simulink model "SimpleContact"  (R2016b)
settings: Solver=ode14x  StartTime=0.0  StopTime=1.5  FixedStep=1e-3  RelTol=1e-3  AbsTol=1e-4  EnableMultiTasking=on
PreLoadFcn:
  | SimpleContact_param
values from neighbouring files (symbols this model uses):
  bn = 50    [SimpleContact_param.m]    (also in BipedRobot_param.m)
  bt = 50    [SimpleContact_param.m]    (also in BipedRobot_param.m)
  kn = 5000    [SimpleContact_param.m]    (also in BipedRobot_param.m)
  kt = 5000    [SimpleContact_param.m]    (also in BipedRobot_param.m)
  mu_d = 0.8    [SimpleContact_param.m]    (also in BipedRobot_param.m)
  mu_s = 2    [SimpleContact_param.m]    (also in BipedRobot_param.m)
  N = 100    [initialize_para.m]    (also in main.m = walk_para.N; walk_parameter.m = 5)
  s = robot_para.s    [kinematics_calc.m]    (also in plot_graph.m; robot_parameter.m = 40; robot_view.m)
  zvt = 1e-3    (= 0.001)    [SimpleContact_param.m]    (also in BipedRobot_param.m)
undefined symbols (not defined in the file or in its folder): deg, kg, m
libraries: mblibv1 x18

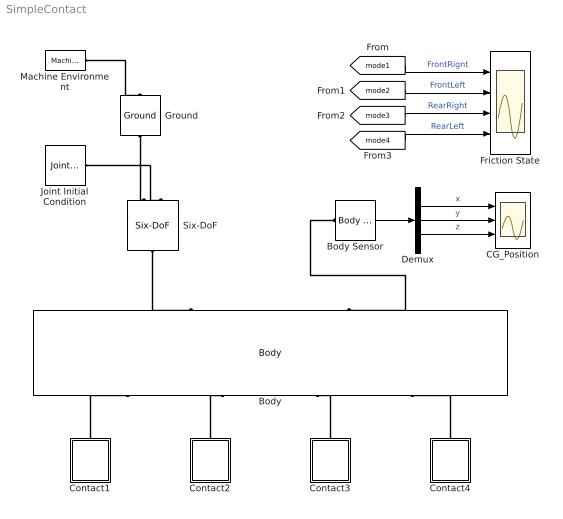
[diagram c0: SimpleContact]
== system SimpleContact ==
  Body : mblibv1/Bodies/Body  LConnTagsString=CS2|CS3|CS4|CS5  RConnTagsString=CG|CS1  UpdateFromCAD=off  DialogClass=MechanicalBodyBlock  Mass=1.4  MassUnits=kg  InertiaUnits=kg*m^2  Inertia=1.4/12*diag([0.065^2+0.02^2 0.095^2+0.02^2 0.095^2+0.065^2])  Shape=Cylinder  ShapeDims=[1 1]  ShapeUnits=m  ShapeUse=false  Density=1  DensityUnits=kg/m^3  DensityUse=false  GraphicsMode=MACHINE_DEFAULT  BodyColorSelMode=MACHINE_DEFAULT  BodyColor=[1;0;0]  AttachedToCS=CG  CG=Right$CG$[0 0 100]$WORLD$WORLD$mm$[30 -30 30]$Euler X-Y-Z$deg$WORLD$true  WorkingFrames=Right$CS1$[0 0 0]$CG$CG$mm$[0 0 0]$Euler X-Y-Z$deg$CG$true#Left$CS2$[47.5 32.5 -10]$CG$CG$mm$[0 0 0]$Euler X-Y-Z$deg$CG$true#Left$CS3$[47.5 -32.5 -10]$CG$CG$mm$[0 0 0]$Euler X-Y-Z$deg$CG$true#Left$CS4$[-47.5 32.5 -10]$CG$CG$mm$[0 0 0]$Euler X-Y-Z$deg$CG$true#Left$CS5$[-47.5 -32.5 -10]$CG$CG$mm$[0 0 0]$Euler X-Y-Z$deg$CG$true#Left$CS6$[47.5 32.5 10]$CG$CG$mm$[0 0 0]$Euler X-Y-Z$deg$CG$false#Left$CS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  CGPos=[0 0 100]  CGRot=[30 -30 30]  CS0Pos=[]  CS0Rot=[]  CS1Pos=[0 0 0]  CS1Rot=[0 0 0]  CS2Pos=[47.5 32.5 -10]  CS2Rot=[0 0 0]  CS3Pos=[47.5 -32.5 -10]  CS3Rot=[0 0 0]  CS4Pos=[-47.5 32.5 -10]  CS4Rot=[0 0 0]  CS5Pos=[-47.5 -32.5 -10]  CS5Rot=[0 0 0]  CS6Pos=[47.5 32.5 10]  CS6Rot=[0 0 0]  CS7Pos=[47.5 -32.5 10]  CS7Rot=[0 0 0]  CS8Pos=[-47.5 32.5 10]  CS8Rot=[0 0 0]  CS9Pos=[-47.5 -32.5 10]  CS9Rot=[0 0 0]  CS10Pos=[]  CS10Rot=[]  CS11Pos=[]  CS11Rot=[]  CS12Pos=[]  CS12Rot=[]  CS13Pos=[]  CS13Rot=[]  CS14Pos=[]  CS14Rot=[]  CS15Pos=[]  CS15Rot=[]  CS16Pos=[]  CS16Rot=[]  CS17Pos=[]  CS17Rot=[]  CS18Pos=[]  CS18Rot=[]  CS19Pos=[]  CS19Rot=[]  CS20Pos=[]  CS20Rot=[]
  Body Sensor : mblibv1/Sensors &  Actuators/Body Sensor  UpdateFromCAD=off  PhysicalDomain=Mechanical  PortType=blob  Muxed=off  Pose=off  Angle=on  AngleUnits=deg  ArcVelocity=off  ArcVelocityUnits=deg/s  ArcAcceleration=off  ArcAccelerationUnits=deg/s^2  CoordPosition=on  CoordPositionUnits=m  Velocity=off  VelocityUnits=m/s  Acceleration=off  AccelerationUnits=m/s^2  Quaternion=on  QuaternionDT=off  QuaternionDDT=off  QuaternionUnits=off  OutputVector=[1]  ActiveIO=on  Width=3  DialogClass=MechanicalSensorBlock  ReferenceFrame=Absolute (World)
  CG_Position : Scope  NumInputPorts=3
  Contact1 : Subsystem
  Contact2 : Subsystem
  Contact3 : Subsystem
  Contact4 : Subsystem
  Demux : Demux  Outputs=3
  Friction State : Scope  NumInputPorts=4
  Ground : mblibv1/Bodies/Ground  UpdateFromCAD=off  LeftPortType=env  RightPortType=workingframe  PhysicalDomain=Mechanical  DialogClass=GroundBlock  CoordPosition=[0 0 100]  CoordPositionUnits=mm  StateVectorMgrId=-1  MachineId=[0 0]  ShowEnvPort=on  ParameterChecksum=[3259088758, 540082064, 4123154655, 1080498542]  TopologyChecksum=[699796033, 4002488209, 2602477049, 3618171501]
  Joint Initial Condition : mblibv1/Sensors &  Actuators/Joint Initial Condition  UpdateFromCAD=off  LeftPortType=blob  RightPortType=blob  PhysicalDomain=mechanical  DialogClass=InitialConditionBlock  InitialConditions=P1$true$0$m$rad$5$m/s$rad/s#P2$true$0$m$rad$0$m/s$rad/s#P3$true$0$m$rad$-0.5$m/s$rad/s#R1$false$0$m$rad$0$m/s$rad/s#R2$false$0$m$rad$0$m/s$rad/s#R3$false$0$m$rad$0$m/s$rad/s#S$false$0$m$rad$0$m/s$rad/s  P1PIC=0  P1VIC=5  P2PIC=0  P2VIC=0  P3PIC=0  P3VIC=-0.5  R1PIC=0  R1VIC=0  R2PIC=0  R2VIC=0  R3PIC=0  R3VIC=0  SPIC=0  SVIC=0
  Machine Environment : mblibv1/Bodies/Machine Environment  Tag=Factory ground  PortType=env  PhysicalDomain=Mechanical  DialogTemplateClass=MECH.MachineEnvironment  SyncWhenCopied=off  Gravity=[0 0 -9.81]  GravityUnits=m/s^2  GravityAsSignal=off  Dimensionality=Auto-detect  AnalysisType=Forward dynamics  LinearAssemblyTolerance=1e-3  LinearAssemblyToleranceUnits=m  AngularAssemblyTolerance=1e-3  AngularAssemblyToleranceUnits=rad  ConstraintSolverType=Stabilizing  ConstraintRelTolerance=1e-4  ConstraintAbsTolerance=1e-4  UseRobustSingularityHandling=off  RedundancyAnalysisToleranceType=Automatically select tolerance  RedundancyAnalysisTolerance=1e-14  StatePerturbationType=Fixed  PerturbationSize=1e-5  VisualizeMachine=on  BodyVisualizationType=Use model default body geometries  BodyColorSelMode=Use model default  DefaultBodyColor=[1 0 0]
  Six-DoF : mblibv1/Joints/Six-DoF  LConnTagsString=__newl0|SA1  RConnTagsString=__newr0  UpdateFromCAD=off  NumSAPorts=1  CutJoint=off  MarkAsCut=off  Primitives=prismatic_prismatic_prismatic_spherical  PrimitiveProps=P1$World$[1 0 0]$prismatic#P2$World$[0 1 0]$prismatic#P3$World$[0 0 1]$prismatic#S$World$[0 0 0]$spherical  DialogClass=JointBlock  P1Axis=[1 0 0]  P2Axis=[0 1 0]  P3Axis=[0 0 1]  SAxis=[0 0 0]
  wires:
  Demux/1 -> CG_Position/1  "x"
  Demux/2 -> CG_Position/2  "y"
  Demux/3 -> CG_Position/3  "z"
  Body Sensor/1 -> Demux/1
  [mode1] -> Friction State/1  "FrontRignt"
  [mode2] -> Friction State/2  "FrontLeft"
  [mode3] -> Friction State/3  "RearRight"
  [mode4] -> Friction State/4  "RearLeft"
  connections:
  Ground/RConn1 -- Six-DoF/LConn1
  Joint Initial Condition/RConn1 -- Six-DoF/LConn2
  Machine Environment/RConn1 -- Ground/LConn1
  Contact1/RConn1 -- Body/LConn1
  Contact2/RConn1 -- Body/LConn2
  Contact3/RConn1 -- Body/LConn3
  Contact4/RConn1 -- Body/LConn4
  Six-DoF/RConn1 -- Body/RConn1
  Body Sensor/LConn1 -- Body/RConn2

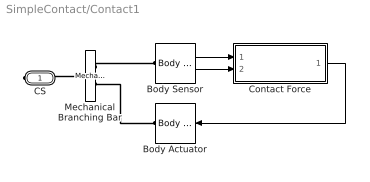
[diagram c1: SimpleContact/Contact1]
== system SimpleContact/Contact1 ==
  Body Actuator : mblibv1/Sensors &  Actuators/Body Actuator  UpdateFromCAD=off  PhysicalDomain=Mechanical  PortType=blob  ActuationStyle=Force  AngleUnits=deg  ArcVelocityUnits=deg/s  ArcAccelerationUnits=deg/s^2  CoordPositionUnits=m  VelocityUnits=m/s  AccelerationUnits=m/s^2  ForceUnits=N  TorqueUnits=N-m  ActiveIO=on  Width=3  DialogClass=MechanicalActuatorBlock  ReferenceFrame=Absolute (World)  Angle=off  CoordPosition=on  Force=on  Torque=off
  Body Sensor : mblibv1/Sensors &  Actuators/Body Sensor  UpdateFromCAD=off  PhysicalDomain=Mechanical  PortType=blob  Muxed=off  Pose=off  Angle=on  AngleUnits=deg  ArcVelocity=off  ArcVelocityUnits=deg/s  ArcAcceleration=off  ArcAccelerationUnits=deg/s^2  CoordPosition=on  CoordPositionUnits=m  Velocity=on  VelocityUnits=m/s  Acceleration=off  AccelerationUnits=m/s^2  Quaternion=on  QuaternionDT=off  QuaternionDDT=off  QuaternionUnits=off  OutputVector=[ 3 3 ]  ActiveIO=on  Width=6  DialogClass=MechanicalSensorBlock  ReferenceFrame=Absolute (World)
  Contact Force : Subsystem
  Mechanical Branching Bar : mblibv1/Utilities/Mechanical Branching Bar  LConnTagsString=_newl0  RConnTagsString=SA0|SA1  UpdateFromCAD=off  DialogClass=MechanicalBranchingBarBlock  NumSAPorts=2
  CS : PMIOPort  Port=1  Side=Right
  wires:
  Contact Force/1(force) -> Body Actuator/1
  Body Sensor/2 -> Contact Force/2(vel)
  Body Sensor/1 -> Contact Force/1(pos)
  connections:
  CS/RConn1 -- Mechanical Branching Bar/LConn1
  Mechanical Branching Bar/RConn2 -- Body Actuator/RConn1
  Mechanical Branching Bar/RConn1 -- Body Sensor/LConn1

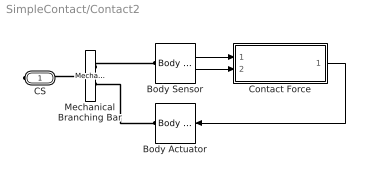
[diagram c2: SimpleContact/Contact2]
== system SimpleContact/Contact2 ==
  Body Actuator : mblibv1/Sensors &  Actuators/Body Actuator  UpdateFromCAD=off  PhysicalDomain=Mechanical  PortType=blob  ActuationStyle=Force  AngleUnits=deg  ArcVelocityUnits=deg/s  ArcAccelerationUnits=deg/s^2  CoordPositionUnits=m  VelocityUnits=m/s  AccelerationUnits=m/s^2  ForceUnits=N  TorqueUnits=N-m  ActiveIO=on  Width=3  DialogClass=MechanicalActuatorBlock  ReferenceFrame=Absolute (World)  Angle=off  CoordPosition=on  Force=on  Torque=off
  Body Sensor : mblibv1/Sensors &  Actuators/Body Sensor  UpdateFromCAD=off  PhysicalDomain=Mechanical  PortType=blob  Muxed=off  Pose=off  Angle=on  AngleUnits=deg  ArcVelocity=off  ArcVelocityUnits=deg/s  ArcAcceleration=off  ArcAccelerationUnits=deg/s^2  CoordPosition=on  CoordPositionUnits=m  Velocity=on  VelocityUnits=m/s  Acceleration=off  AccelerationUnits=m/s^2  Quaternion=on  QuaternionDT=off  QuaternionDDT=off  QuaternionUnits=off  OutputVector=[ 3 3 ]  ActiveIO=on  Width=6  DialogClass=MechanicalSensorBlock  ReferenceFrame=Absolute (World)
  Contact Force : Subsystem
  Mechanical Branching Bar : mblibv1/Utilities/Mechanical Branching Bar  LConnTagsString=_newl0  RConnTagsString=SA0|SA1  UpdateFromCAD=off  DialogClass=MechanicalBranchingBarBlock  NumSAPorts=2
  CS : PMIOPort  Port=1  Side=Right
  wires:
  Body Sensor/1 -> Contact Force/1(pos)
  Body Sensor/2 -> Contact Force/2(vel)
  Contact Force/1(force) -> Body Actuator/1
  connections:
  Mechanical Branching Bar/RConn1 -- Body Sensor/LConn1
  Mechanical Branching Bar/RConn2 -- Body Actuator/RConn1
  CS/RConn1 -- Mechanical Branching Bar/LConn1

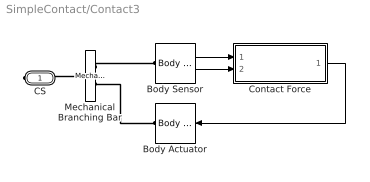
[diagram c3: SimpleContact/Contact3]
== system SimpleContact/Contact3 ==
  Body Actuator : mblibv1/Sensors &  Actuators/Body Actuator  UpdateFromCAD=off  PhysicalDomain=Mechanical  PortType=blob  ActuationStyle=Force  AngleUnits=deg  ArcVelocityUnits=deg/s  ArcAccelerationUnits=deg/s^2  CoordPositionUnits=m  VelocityUnits=m/s  AccelerationUnits=m/s^2  ForceUnits=N  TorqueUnits=N-m  ActiveIO=on  Width=3  DialogClass=MechanicalActuatorBlock  ReferenceFrame=Absolute (World)  Angle=off  CoordPosition=on  Force=on  Torque=off
  Body Sensor : mblibv1/Sensors &  Actuators/Body Sensor  UpdateFromCAD=off  PhysicalDomain=Mechanical  PortType=blob  Muxed=off  Pose=off  Angle=on  AngleUnits=deg  ArcVelocity=off  ArcVelocityUnits=deg/s  ArcAcceleration=off  ArcAccelerationUnits=deg/s^2  CoordPosition=on  CoordPositionUnits=m  Velocity=on  VelocityUnits=m/s  Acceleration=off  AccelerationUnits=m/s^2  Quaternion=on  QuaternionDT=off  QuaternionDDT=off  QuaternionUnits=off  OutputVector=[ 3 3 ]  ActiveIO=on  Width=6  DialogClass=MechanicalSensorBlock  ReferenceFrame=Absolute (World)
  Contact Force : Subsystem
  Mechanical Branching Bar : mblibv1/Utilities/Mechanical Branching Bar  LConnTagsString=_newl0  RConnTagsString=SA0|SA1  UpdateFromCAD=off  DialogClass=MechanicalBranchingBarBlock  NumSAPorts=2
  CS : PMIOPort  Port=1  Side=Right
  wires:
  Body Sensor/1 -> Contact Force/1(pos)
  Body Sensor/2 -> Contact Force/2(vel)
  Contact Force/1(force) -> Body Actuator/1
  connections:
  Mechanical Branching Bar/RConn1 -- Body Sensor/LConn1
  Mechanical Branching Bar/RConn2 -- Body Actuator/RConn1
  CS/RConn1 -- Mechanical Branching Bar/LConn1

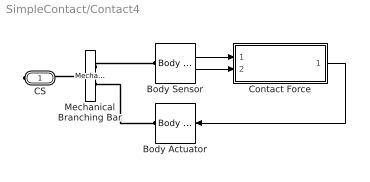
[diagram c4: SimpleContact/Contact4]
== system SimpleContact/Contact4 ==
  Body Actuator : mblibv1/Sensors &  Actuators/Body Actuator  UpdateFromCAD=off  PhysicalDomain=Mechanical  PortType=blob  ActuationStyle=Force  AngleUnits=deg  ArcVelocityUnits=deg/s  ArcAccelerationUnits=deg/s^2  CoordPositionUnits=m  VelocityUnits=m/s  AccelerationUnits=m/s^2  ForceUnits=N  TorqueUnits=N-m  ActiveIO=on  Width=3  DialogClass=MechanicalActuatorBlock  ReferenceFrame=Absolute (World)  Angle=off  CoordPosition=on  Force=on  Torque=off
  Body Sensor : mblibv1/Sensors &  Actuators/Body Sensor  UpdateFromCAD=off  PhysicalDomain=Mechanical  PortType=blob  Muxed=off  Pose=off  Angle=on  AngleUnits=deg  ArcVelocity=off  ArcVelocityUnits=deg/s  ArcAcceleration=off  ArcAccelerationUnits=deg/s^2  CoordPosition=on  CoordPositionUnits=m  Velocity=on  VelocityUnits=m/s  Acceleration=off  AccelerationUnits=m/s^2  Quaternion=on  QuaternionDT=off  QuaternionDDT=off  QuaternionUnits=off  OutputVector=[ 3 3 ]  ActiveIO=on  Width=6  DialogClass=MechanicalSensorBlock  ReferenceFrame=Absolute (World)
  Contact Force : Subsystem
  Mechanical Branching Bar : mblibv1/Utilities/Mechanical Branching Bar  LConnTagsString=_newl0  RConnTagsString=SA0|SA1  UpdateFromCAD=off  DialogClass=MechanicalBranchingBarBlock  NumSAPorts=2
  CS : PMIOPort  Port=1  Side=Right
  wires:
  Contact Force/1(force) -> Body Actuator/1
  Body Sensor/2 -> Contact Force/2(vel)
  Body Sensor/1 -> Contact Force/1(pos)
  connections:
  CS/RConn1 -- Mechanical Branching Bar/LConn1
  Mechanical Branching Bar/RConn2 -- Body Actuator/RConn1
  Mechanical Branching Bar/RConn1 -- Body Sensor/LConn1

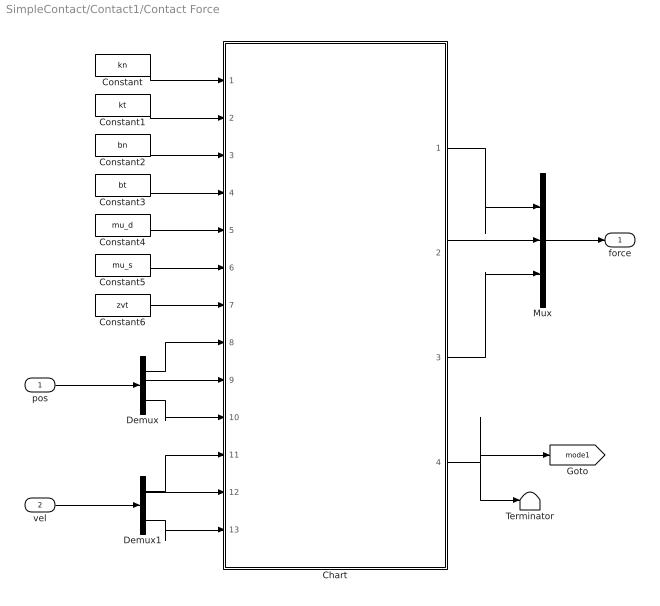
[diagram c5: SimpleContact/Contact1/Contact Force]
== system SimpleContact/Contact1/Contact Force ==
  pos : Inport
  vel : Inport  Port=2
  Chart : Stateflow chart  TreatAsAtomicUnit=on
  Constant : Constant  Value=kn
  Constant1 : Constant  Value=kt
  Constant2 : Constant  Value=bn
  Constant3 : Constant  Value=bt
  Constant4 : Constant  Value=mu_d
  Constant5 : Constant  Value=mu_s
  Constant6 : Constant  Value=zvt
  Demux : Demux  Outputs=3
  Demux1 : Demux  Outputs=3
  Mux : Mux  Inputs=3
  Terminator : Terminator
  force : Outport  InitialOutput=0
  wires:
  Constant6/1 -> Chart/7(zvt)
  Constant5/1 -> Chart/6(mu_s)
  Constant4/1 -> Chart/5(mu_d)
  Constant3/1 -> Chart/4(bt)
  Constant2/1 -> Chart/3(bn)
  Constant1/1 -> Chart/2(kt)
  Constant/1 -> Chart/1(kn)
  Mux/1 -> force/1
  Chart/4(mode) -> [mode1], Terminator/1
  Demux/1 -> Chart/8(px)
  Demux/2 -> Chart/9(py)
  Demux/3 -> Chart/10(pn)
  Demux1/1 -> Chart/11(dpx)
  Demux1/2 -> Chart/12(dpy)
  Demux1/3 -> Chart/13(dpn)
  pos/1 -> Demux/1
  vel/1 -> Demux1/1
  Chart/1(Fx) -> Mux/1
  Chart/2(Fy) -> Mux/2
  Chart/3(Fn) -> Mux/3

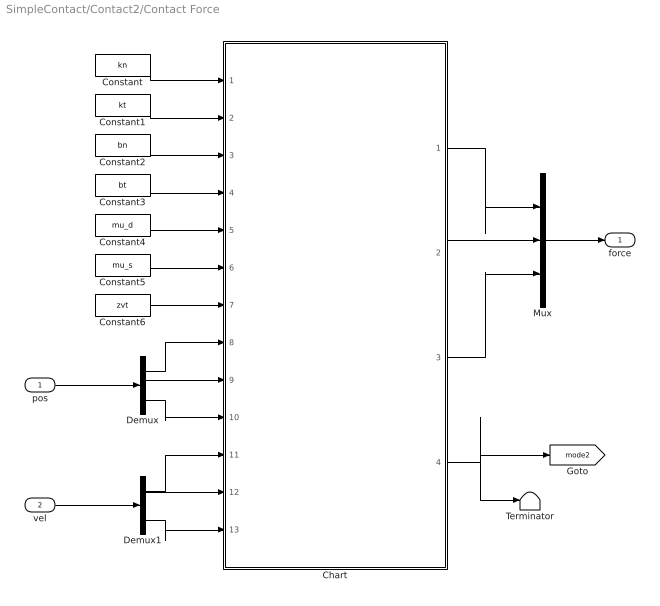
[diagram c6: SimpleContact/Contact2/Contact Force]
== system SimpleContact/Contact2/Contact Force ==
  pos : Inport
  vel : Inport  Port=2
  Chart : Stateflow chart  TreatAsAtomicUnit=on
  Constant : Constant  Value=kn
  Constant1 : Constant  Value=kt
  Constant2 : Constant  Value=bn
  Constant3 : Constant  Value=bt
  Constant4 : Constant  Value=mu_d
  Constant5 : Constant  Value=mu_s
  Constant6 : Constant  Value=zvt
  Demux : Demux  Outputs=3
  Demux1 : Demux  Outputs=3
  Mux : Mux  Inputs=3
  Terminator : Terminator
  force : Outport  InitialOutput=0
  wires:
  Chart/3(Fn) -> Mux/3
  Chart/2(Fy) -> Mux/2
  Chart/1(Fx) -> Mux/1
  vel/1 -> Demux1/1
  pos/1 -> Demux/1
  Demux1/3 -> Chart/13(dpn)
  Demux1/2 -> Chart/12(dpy)
  Demux1/1 -> Chart/11(dpx)
  Demux/3 -> Chart/10(pn)
  Demux/2 -> Chart/9(py)
  Demux/1 -> Chart/8(px)
  Chart/4(mode) -> Terminator/1, [mode2]
  Mux/1 -> force/1
  Constant/1 -> Chart/1(kn)
  Constant1/1 -> Chart/2(kt)
  Constant2/1 -> Chart/3(bn)
  Constant3/1 -> Chart/4(bt)
  Constant4/1 -> Chart/5(mu_d)
  Constant5/1 -> Chart/6(mu_s)
  Constant6/1 -> Chart/7(zvt)

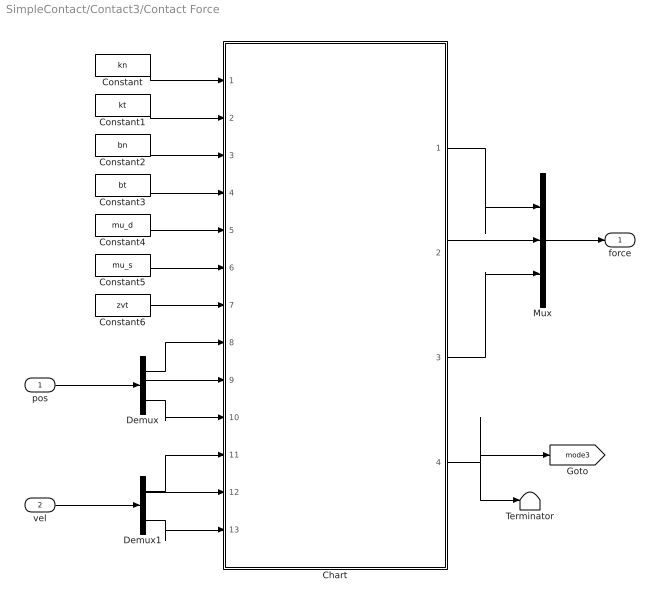
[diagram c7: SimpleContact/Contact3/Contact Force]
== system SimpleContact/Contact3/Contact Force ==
  pos : Inport
  vel : Inport  Port=2
  Chart : Stateflow chart  TreatAsAtomicUnit=on
  Constant : Constant  Value=kn
  Constant1 : Constant  Value=kt
  Constant2 : Constant  Value=bn
  Constant3 : Constant  Value=bt
  Constant4 : Constant  Value=mu_d
  Constant5 : Constant  Value=mu_s
  Constant6 : Constant  Value=zvt
  Demux : Demux  Outputs=3
  Demux1 : Demux  Outputs=3
  Mux : Mux  Inputs=3
  Terminator : Terminator
  force : Outport  InitialOutput=0
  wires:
  Chart/3(Fn) -> Mux/3
  Chart/2(Fy) -> Mux/2
  Chart/1(Fx) -> Mux/1
  vel/1 -> Demux1/1
  pos/1 -> Demux/1
  Demux1/3 -> Chart/13(dpn)
  Demux1/2 -> Chart/12(dpy)
  Demux1/1 -> Chart/11(dpx)
  Demux/3 -> Chart/10(pn)
  Demux/2 -> Chart/9(py)
  Demux/1 -> Chart/8(px)
  Chart/4(mode) -> Terminator/1, [mode3]
  Mux/1 -> force/1
  Constant/1 -> Chart/1(kn)
  Constant1/1 -> Chart/2(kt)
  Constant2/1 -> Chart/3(bn)
  Constant3/1 -> Chart/4(bt)
  Constant4/1 -> Chart/5(mu_d)
  Constant5/1 -> Chart/6(mu_s)
  Constant6/1 -> Chart/7(zvt)

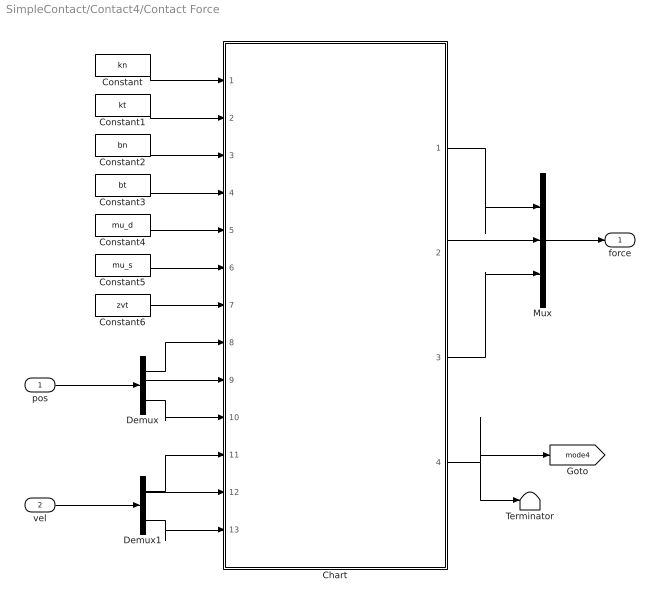
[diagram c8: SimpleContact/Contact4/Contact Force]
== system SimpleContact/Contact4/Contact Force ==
  pos : Inport
  vel : Inport  Port=2
  Chart : Stateflow chart  TreatAsAtomicUnit=on
  Constant : Constant  Value=kn
  Constant1 : Constant  Value=kt
  Constant2 : Constant  Value=bn
  Constant3 : Constant  Value=bt
  Constant4 : Constant  Value=mu_d
  Constant5 : Constant  Value=mu_s
  Constant6 : Constant  Value=zvt
  Demux : Demux  Outputs=3
  Demux1 : Demux  Outputs=3
  Mux : Mux  Inputs=3
  Terminator : Terminator
  force : Outport  InitialOutput=0
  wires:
  Constant6/1 -> Chart/7(zvt)
  Constant5/1 -> Chart/6(mu_s)
  Constant4/1 -> Chart/5(mu_d)
  Constant3/1 -> Chart/4(bt)
  Constant2/1 -> Chart/3(bn)
  Constant1/1 -> Chart/2(kt)
  Constant/1 -> Chart/1(kn)
  Mux/1 -> force/1
  Chart/4(mode) -> [mode4], Terminator/1
  Demux/1 -> Chart/8(px)
  Demux/2 -> Chart/9(py)
  Demux/3 -> Chart/10(pn)
  Demux1/1 -> Chart/11(dpx)
  Demux1/2 -> Chart/12(dpy)
  Demux1/3 -> Chart/13(dpn)
  pos/1 -> Demux/1
  vel/1 -> Demux1/1
  Chart/1(Fx) -> Mux/1
  Chart/2(Fy) -> Mux/2
  Chart/3(Fn) -> Mux/3

== stateflow chart SimpleContact/Contact2/Contact
Force/Chart ==
  state No_Contact/
    state 非接触状態 [group]
    (default) -> (junction 48) : { mode = 1;  /* 垂直力、摩擦力ともにゼロ */ Fn = 0; Fx = 0; Fy = 0; }
  state Sticking/
    state 固着状態 [group]
    Sticking -> (junction 53) : { /* 垂直力計算 */ Fn = -(kn*pn+bn*dpn); }
    (default) -> (junction 52) : { mode = 4;  /* 垂直力計算 */ Fn = -(kn*pn+bn*dpn); }
    (junction 52) -> (junction 53)
    (junction 53) -> (junction 54) : [ Fn < 0 ]
    (junction 53) -> (junction 41) : { /* 静止摩擦力計算 */ Fx = -(kt*(px-ax)+bt*dpx); Fy = -(kt*(py-ay)+bt*dpy);  /* 摩擦力ベクトルの大きさ */ norm_Ft = sqrt(Fx^2+Fy^2); }
    (junction 54) -> (junction 47) : { mode = 6;  /* 垂直力が負のときの処理 垂直力、摩擦力をゼロへ */ Fn = 0; Fx = 0; Fy = 0; }
    (junction 41) -> (junction 40) : [ norm_Ft > mu_s*Fn ]
    (junction 41) -> (junction 39)
    (junction 40) -> (junction 38) : { mode = 5;  /* 静止摩擦力計算 */ Fx = -mu_s*Fn*Fx/norm_Ft; Fy = -mu_s*Fn*Fy/norm_Ft; }
    (junction 38) -> (junction 39)
    (junction 47) -> (junction 38)
    (junction 39) -> (junction 56)
  state Sliding/
    state 滑り状態 [group]
    Sliding -> (junction 43) : { mode = 2;  /* 垂直力計算 */ Fn = -(kn*pn+bn*dpn); }
    (default) -> (junction 42) : { mode = 2;  /* 垂直力計算 */ Fn = -(kn*pn+bn*dpn); }
    (junction 42) -> (junction 43)
    (junction 43) -> (junction 44) : [ Fn < 0 ]
    (junction 43) -> (junction 45) : { /* 接線方向速度ベクトルの大きさ */ norm_dpt = sqrt(dpx^2+dpy^2); }
    (junction 44) -> (junction 46) : { mode = 6;  /* 垂直力が負のときの処理 垂直力、摩擦力をゼロへ */ Fn = 0; Fx = 0; Fy = 0; }
    (junction 45) -> (junction 49) : [ norm_dpt <= zvt ]
    (junction 45) -> (junction 51) : { /* 動摩擦力計算 */ Fx = -mu_d*Fn*dpx/norm_dpt; Fy = -mu_d*Fn*dpy/norm_dpt; }
    (junction 49) -> (junction 50) : { mode = 3;  /* 動摩擦力計算 */ Fx = -mu_d*Fn*dpx/zvt; Fy = -mu_d*Fn*dpy/zvt;  /* アンカーポイント設定 */ ax = px; ay = py; }
    (junction 50) -> (junction 51)
    (junction 46) -> (junction 50)
    (junction 51) -> (junction 55)
  (default) -> No_Contact
  Sliding -> No_Contact : [pn >= 0 ]
  No_Contact -> Sliding : [ pn < 0 ]
  Sticking -> No_Contact : [ pn >= 0 ]
  Sliding -> Sticking : [ pn < 0 ... && mode == 3 ]
  Sticking -> Sliding : [ pn < 0 ... && (mode == 5 || mode == 6) ]
  data: Fx output double; Fy output double; kn input =kn; kt input =kt; bn input =bn; bt input =bt; mu_d input =mu_d; mu_s input =mu_s; zvt input =zvt; px input; py input; pn input; dpx input; dpy input; Fn output double; dpn input; norm_dpt local double; norm_Ft local double; mode output double; ax local double; ay local double

== stateflow chart SimpleContact/Contact3/Contact
Force/Chart ==
  state No_Contact/
    state 非接触状態 [group]
    (default) -> (junction 48) : { mode = 1;  /* 垂直力、摩擦力ともにゼロ */ Fn = 0; Fx = 0; Fy = 0; }
  state Sticking/
    state 固着状態 [group]
    Sticking -> (junction 53) : { /* 垂直力計算 */ Fn = -(kn*pn+bn*dpn); }
    (default) -> (junction 52) : { mode = 4;  /* 垂直力計算 */ Fn = -(kn*pn+bn*dpn); }
    (junction 52) -> (junction 53)
    (junction 53) -> (junction 54) : [ Fn < 0 ]
    (junction 53) -> (junction 41) : { /* 静止摩擦力計算 */ Fx = -(kt*(px-ax)+bt*dpx); Fy = -(kt*(py-ay)+bt*dpy);  /* 摩擦力ベクトルの大きさ */ norm_Ft = sqrt(Fx^2+Fy^2); }
    (junction 54) -> (junction 47) : { mode = 6;  /* 垂直力が負のときの処理 垂直力、摩擦力をゼロへ */ Fn = 0; Fx = 0; Fy = 0; }
    (junction 41) -> (junction 40) : [ norm_Ft > mu_s*Fn ]
    (junction 41) -> (junction 39)
    (junction 40) -> (junction 38) : { mode = 5;  /* 静止摩擦力計算 */ Fx = -mu_s*Fn*Fx/norm_Ft; Fy = -mu_s*Fn*Fy/norm_Ft; }
    (junction 38) -> (junction 39)
    (junction 47) -> (junction 38)
    (junction 39) -> (junction 56)
  state Sliding/
    state 滑り状態 [group]
    Sliding -> (junction 43) : { mode = 2;  /* 垂直力計算 */ Fn = -(kn*pn+bn*dpn); }
    (default) -> (junction 42) : { mode = 2;  /* 垂直力計算 */ Fn = -(kn*pn+bn*dpn); }
    (junction 42) -> (junction 43)
    (junction 43) -> (junction 44) : [ Fn < 0 ]
    (junction 43) -> (junction 45) : { /* 接線方向速度ベクトルの大きさ */ norm_dpt = sqrt(dpx^2+dpy^2); }
    (junction 44) -> (junction 46) : { mode = 6;  /* 垂直力が負のときの処理 垂直力、摩擦力をゼロへ */ Fn = 0; Fx = 0; Fy = 0; }
    (junction 45) -> (junction 49) : [ norm_dpt <= zvt ]
    (junction 45) -> (junction 51) : { /* 動摩擦力計算 */ Fx = -mu_d*Fn*dpx/norm_dpt; Fy = -mu_d*Fn*dpy/norm_dpt; }
    (junction 49) -> (junction 50) : { mode = 3;  /* 動摩擦力計算 */ Fx = -mu_d*Fn*dpx/zvt; Fy = -mu_d*Fn*dpy/zvt;  /* アンカーポイント設定 */ ax = px; ay = py; }
    (junction 50) -> (junction 51)
    (junction 46) -> (junction 50)
    (junction 51) -> (junction 55)
  (default) -> No_Contact
  Sliding -> No_Contact : [pn >= 0 ]
  No_Contact -> Sliding : [ pn < 0 ]
  Sticking -> No_Contact : [ pn >= 0 ]
  Sliding -> Sticking : [ pn < 0 ... && mode == 3 ]
  Sticking -> Sliding : [ pn < 0 ... && (mode == 5 || mode == 6) ]
  data: Fx output double; Fy output double; kn input =kn; kt input =kt; bn input =bn; bt input =bt; mu_d input =mu_d; mu_s input =mu_s; zvt input =zvt; px input; py input; pn input; dpx input; dpy input; Fn output double; dpn input; norm_dpt local double; norm_Ft local double; mode output double; ax local double; ay local double

== stateflow chart SimpleContact/Contact4/Contact
Force/Chart ==
  state No_Contact/
    state 非接触状態 [group]
    (default) -> (junction 48) : { mode = 1;  /* 垂直力、摩擦力ともにゼロ */ Fn = 0; Fx = 0; Fy = 0; }
  state Sticking/
    state 固着状態 [group]
    Sticking -> (junction 53) : { /* 垂直力計算 */ Fn = -(kn*pn+bn*dpn); }
    (default) -> (junction 52) : { mode = 4;  /* 垂直力計算 */ Fn = -(kn*pn+bn*dpn); }
    (junction 52) -> (junction 53)
    (junction 53) -> (junction 54) : [ Fn < 0 ]
    (junction 53) -> (junction 41) : { /* 静止摩擦力計算 */ Fx = -(kt*(px-ax)+bt*dpx); Fy = -(kt*(py-ay)+bt*dpy);  /* 摩擦力ベクトルの大きさ */ norm_Ft = sqrt(Fx^2+Fy^2); }
    (junction 54) -> (junction 47) : { mode = 6;  /* 垂直力が負のときの処理 垂直力、摩擦力をゼロへ */ Fn = 0; Fx = 0; Fy = 0; }
    (junction 41) -> (junction 40) : [ norm_Ft > mu_s*Fn ]
    (junction 41) -> (junction 39)
    (junction 40) -> (junction 38) : { mode = 5;  /* 静止摩擦力計算 */ Fx = -mu_s*Fn*Fx/norm_Ft; Fy = -mu_s*Fn*Fy/norm_Ft; }
    (junction 38) -> (junction 39)
    (junction 47) -> (junction 38)
    (junction 39) -> (junction 56)
  state Sliding/
    state 滑り状態 [group]
    Sliding -> (junction 43) : { mode = 2;  /* 垂直力計算 */ Fn = -(kn*pn+bn*dpn); }
    (default) -> (junction 42) : { mode = 2;  /* 垂直力計算 */ Fn = -(kn*pn+bn*dpn); }
    (junction 42) -> (junction 43)
    (junction 43) -> (junction 44) : [ Fn < 0 ]
    (junction 43) -> (junction 45) : { /* 接線方向速度ベクトルの大きさ */ norm_dpt = sqrt(dpx^2+dpy^2); }
    (junction 44) -> (junction 46) : { mode = 6;  /* 垂直力が負のときの処理 垂直力、摩擦力をゼロへ */ Fn = 0; Fx = 0; Fy = 0; }
    (junction 45) -> (junction 49) : [ norm_dpt <= zvt ]
    (junction 45) -> (junction 51) : { /* 動摩擦力計算 */ Fx = -mu_d*Fn*dpx/norm_dpt; Fy = -mu_d*Fn*dpy/norm_dpt; }
    (junction 49) -> (junction 50) : { mode = 3;  /* 動摩擦力計算 */ Fx = -mu_d*Fn*dpx/zvt; Fy = -mu_d*Fn*dpy/zvt;  /* アンカーポイント設定 */ ax = px; ay = py; }
    (junction 50) -> (junction 51)
    (junction 46) -> (junction 50)
    (junction 51) -> (junction 55)
  (default) -> No_Contact
  Sliding -> No_Contact : [pn >= 0 ]
  No_Contact -> Sliding : [ pn < 0 ]
  Sticking -> No_Contact : [ pn >= 0 ]
  Sliding -> Sticking : [ pn < 0 ... && mode == 3 ]
  Sticking -> Sliding : [ pn < 0 ... && (mode == 5 || mode == 6) ]
  data: Fx output double; Fy output double; kn input =kn; kt input =kt; bn input =bn; bt input =bt; mu_d input =mu_d; mu_s input =mu_s; zvt input =zvt; px input; py input; pn input; dpx input; dpy input; Fn output double; dpn input; norm_dpt local double; norm_Ft local double; mode output double; ax local double; ay local double

== stateflow chart SimpleContact/Contact1/Contact
Force/Chart ==
  state No_Contact/
    state 非接触状態 [group]
    (default) -> (junction 48) : { mode = 1;  /* 垂直力、摩擦力ともにゼロ */ Fn = 0; Fx = 0; Fy = 0; }
  state Sticking/
    state 固着状態 [group]
    Sticking -> (junction 53) : { /* 垂直力計算 */ Fn = -(kn*pn+bn*dpn); }
    (default) -> (junction 52) : { mode = 4;  /* 垂直力計算 */ Fn = -(kn*pn+bn*dpn); }
    (junction 52) -> (junction 53)
    (junction 53) -> (junction 54) : [ Fn < 0 ]
    (junction 53) -> (junction 41) : { /* 静止摩擦力計算 */ Fx = -(kt*(px-ax)+bt*dpx); Fy = -(kt*(py-ay)+bt*dpy);  /* 摩擦力ベクトルの大きさ */ norm_Ft = sqrt(Fx^2+Fy^2); }
    (junction 54) -> (junction 47) : { mode = 6;  /* 垂直力が負のときの処理 垂直力、摩擦力をゼロへ */ Fn = 0; Fx = 0; Fy = 0; }
    (junction 41) -> (junction 40) : [ norm_Ft > mu_s*Fn ]
    (junction 41) -> (junction 39)
    (junction 40) -> (junction 38) : { mode = 5;  /* 静止摩擦力計算 */ Fx = -mu_s*Fn*Fx/norm_Ft; Fy = -mu_s*Fn*Fy/norm_Ft; }
    (junction 38) -> (junction 39)
    (junction 47) -> (junction 38)
    (junction 39) -> (junction 56)
  state Sliding/
    state 滑り状態 [group]
    Sliding -> (junction 43) : { mode = 2;  /* 垂直力計算 */ Fn = -(kn*pn+bn*dpn); }
    (default) -> (junction 42) : { mode = 2;  /* 垂直力計算 */ Fn = -(kn*pn+bn*dpn); }
    (junction 42) -> (junction 43)
    (junction 43) -> (junction 44) : [ Fn < 0 ]
    (junction 43) -> (junction 45) : { /* 接線方向速度ベクトルの大きさ */ norm_dpt = sqrt(dpx^2+dpy^2); }
    (junction 44) -> (junction 46) : { mode = 6;  /* 垂直力が負のときの処理 垂直力、摩擦力をゼロへ */ Fn = 0; Fx = 0; Fy = 0; }
    (junction 45) -> (junction 49) : [ norm_dpt <= zvt ]
    (junction 45) -> (junction 51) : { /* 動摩擦力計算 */ Fx = -mu_d*Fn*dpx/norm_dpt; Fy = -mu_d*Fn*dpy/norm_dpt; }
    (junction 49) -> (junction 50) : { mode = 3;  /* 動摩擦力計算 */ Fx = -mu_d*Fn*dpx/zvt; Fy = -mu_d*Fn*dpy/zvt;  /* アンカーポイント設定 */ ax = px; ay = py; }
    (junction 50) -> (junction 51)
    (junction 46) -> (junction 50)
    (junction 51) -> (junction 55)
  (default) -> No_Contact
  Sliding -> No_Contact : [pn >= 0 ]
  No_Contact -> Sliding : [ pn < 0 ]
  Sticking -> No_Contact : [ pn >= 0 ]
  Sliding -> Sticking : [ pn < 0 ... && mode == 3 ]
  Sticking -> Sliding : [ pn < 0 ... && (mode == 5 || mode == 6) ]
  data: Fx output double; Fy output double; kn input =kn; kt input =kt; bn input =bn; bt input =bt; mu_d input =mu_d; mu_s input =mu_s; zvt input =zvt; px input; py input; pn input; dpx input; dpy input; Fn output double; dpn input; norm_dpt local double; norm_Ft local double; mode output double; ax local double; ay local double
